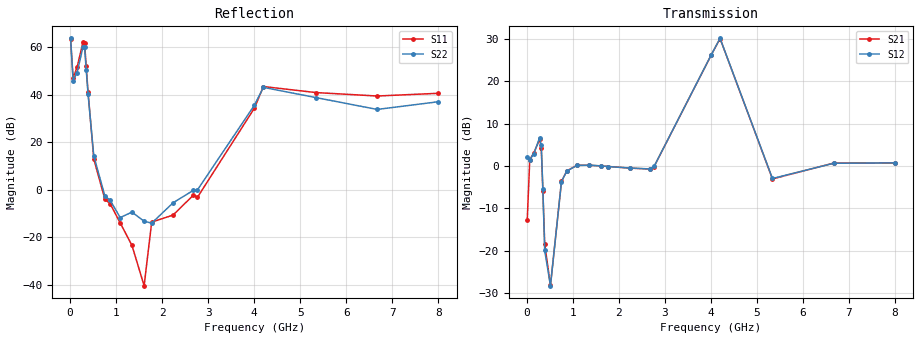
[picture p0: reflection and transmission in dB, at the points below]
!Agilent Technologies,N5230A,US43500312,A.07.50.67
!Agilent N5230A: A.07.50.67
!Date: Tuesday, June 09, 2015 15:40:06
!Correction: S11(Full 2 Port(1,2))
!S21(Full 2 Port(1,2))
!S12(Full 2 Port(1,2))
!S22(Full 2 Port(1,2))
!S2P File: Measurements: S11, S21, S12, S22:
# Hz S  MA  R 50
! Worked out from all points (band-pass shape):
!   1601 points, 10 MHz to 8 GHz, reference 50 ohm
!   highest |S21| = 30.10 dB at 4.2 GHz (marker M1); lowest = -28.2 dB at 514.4 MHz (marker M2)
!   |S21| within 3 dB of the highest: 4.038 GHz to 4.378 GHz (340.5 MHz wide, 8.09 % of centre)
!   lowest |S11| = -40.4 dB at 1.608 GHz (marker M3), VSWR 1.02, Z = 50.6 + j0.78 ohm
!   |S11| at or under -10 dB: 945.9 MHz to 2.252 GHz (1.306 GHz wide, 81.7 % of centre); 2.906 GHz to 3.056 GHz (149.9 MHz wide, 5.03 % of centre)
!   |S22| runs from -14.9 to 63.6 dB; largest |S21 - S12| = 1.1
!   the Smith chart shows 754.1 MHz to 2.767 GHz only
!   S11 on the Smith chart (normalised r, x): 754.1 MHz: 0.27, -0.43; 868.9 MHz: 0.92, -1.13; 1.089 GHz: 1.15, +0.41; 1.773 GHz: 0.84, +0.35; 2.237 GHz: 1.58, -0.50; 2.767 GHz: 0.90, -1.80
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1e7  1490 171.1  0.2285 -63.7  1.258 -12.9  1520 -19.4
6.493125e7  220.2 338.5  1.187 3.5  1.189 1.5  196.5 98.0
1.49825e8  371.9 402.5  1.417 8.7  1.379 9.3  286.7 124.9
2.796625e8  1262 423.9  2.052 26.1  2.159 24.3  988.9 137.6
3.146188e8  1210 451.4  1.645 64.3  1.765 54.6  982.8 167.6
3.49575e8  390.1 472.0  0.5101 93.2  0.5277 81.7  332.8 193.3
3.89525e8  113.5 481.7  0.1191 96.1  0.1003 90.9  103.3 211.8
5.143688e8  4.409 507.4  0.03873 106.6  0.0385 107.1  5.114 286.1
7.540688e8  0.6313 589.7  0.6557 189.0  0.6545 189.1  0.744 456.5
8.68925e8  0.5078 656.5  0.8734 155.0  0.8683 155.0  0.5969 547.7
1.08865e9  0.1989 779.0  1.016 141.1  1.013 141.0  0.2582 663.9
1.343331e9  0.06721 750.4  1.02 145.6  1.02 145.6  0.3362 777.0
1.608e9  0.009527 774.1  0.9994 146.7  1.002 146.7  0.2163 883.7
1.772794e9  0.2071 824.4  0.9841 144.4  0.9818 144.5  0.1969 976.4
2.237212e9  0.2913 689.9  0.9424 136.0  0.9446 136.1  0.5284 1133.6
2.676662e9  0.7627 668.2  0.9178 150.3  0.9211 150.4  0.9646 1232.7
2.76655e9  0.688 670.3  0.984 153.4  0.9868 153.4  0.9869 1250.7
4.005e9  51.81 751.4  20.26 191.9  20.33 192.1  59.73 1533.5
4.199756e9  147.4 688.8  31.97 113.1  32.09 113.3  141.4 1488.3
5.338331e9  110.1 644.6  0.7013 20.0  0.7105 19.7  86.45 1416.7
6.671662e9  93.11 666.2  1.081 22.6  1.075 22.6  48.62 1359.1
8e9  106.2 682.2  1.082 14.6  1.086 14.8  70.55 1319.2
